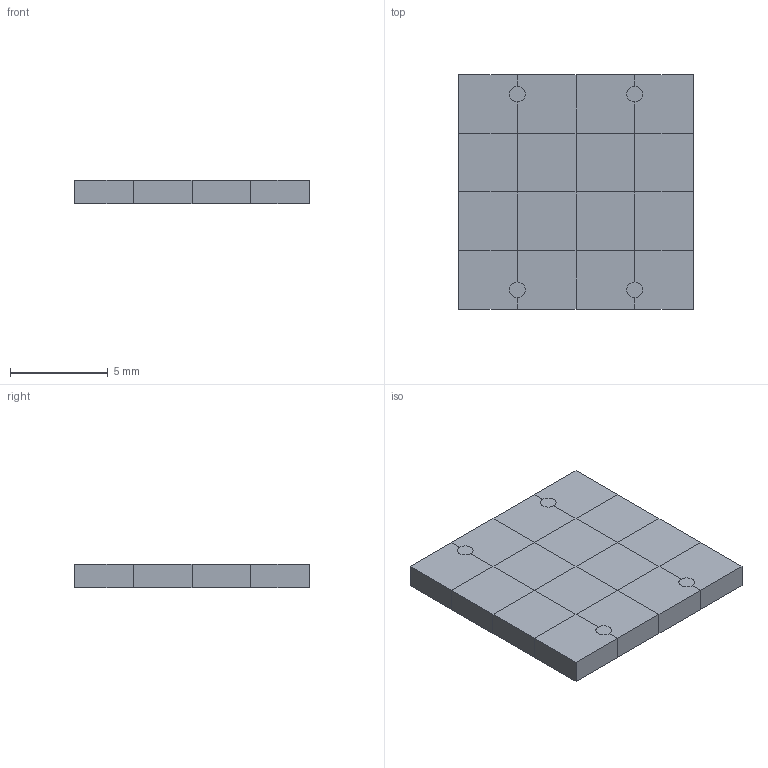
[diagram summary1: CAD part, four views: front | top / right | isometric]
STEP (ISO 10303-21) file: header records copied from the file, then geometry measured from it (millimetres).
FILE_DESCRIPTION(('Open CASCADE Model'),'2;1');
FILE_NAME('Open CASCADE Shape Model','2026-11-20T08:25:56',('Author'),( 'Open CASCADE'),'Open CASCADE STEP processor 7.9','Open CASCADE 7.9' ,'Unknown');
FILE_SCHEMA(('AUTOMOTIVE_DESIGN { 1 0 10303 214 1 1 1 1 }'));
Length unit declared in the file: millimetre
Products named in the file (3): manifold_B7; fluid; solid
Assembly tree (2 placements, depth 2):
  manifold_B7
    fluid
    solid
Bounding box: 12 x 12 x 1.2 mm (x, y, z)
Volume: 172.8 mm3; surface area: 1434.4 mm2
Topology: 2 solids, 2 shells, 1096 faces, 3960 edges, 2194 vertices
Faces by surface type: plane 1088, cylinder 8
Full cylindrical faces by diameter (mm): 0.8 x8
Entity records: 92590 total; most frequent: CARTESIAN_POINT 15221, DIRECTION 14094, LINE 11832, VECTOR 11832, ORIENTED_EDGE 7920, PCURVE 7920, DEFINITIONAL_REPRESENTATION 7920, EDGE_CURVE 3960
One B-rep face of a CAD part: STEP entity #49374.
In plain terms, the planar face has unit normal (0, 0, 1).
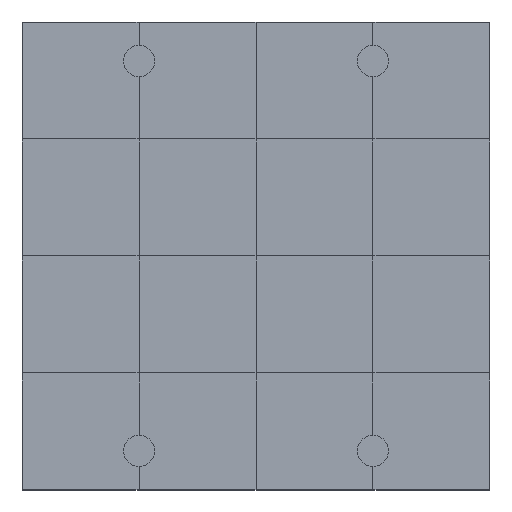
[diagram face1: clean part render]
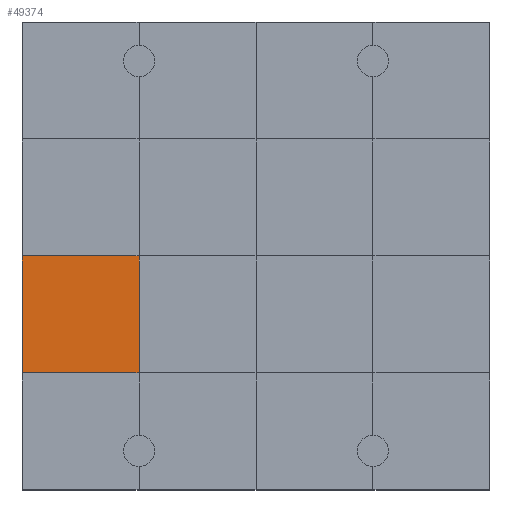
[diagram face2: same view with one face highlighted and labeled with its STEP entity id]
Its self-contained STEP definition (entity closure, numbers rounded to 3 decimals):
#48924 = VERTEX_POINT('',#48925);
#48925 = CARTESIAN_POINT('',(0.,3.,1.2));
#48939 = PLANE('',#48940);
#48940 = AXIS2_PLACEMENT_3D('',#48941,#48942,#48943);
#48941 = CARTESIAN_POINT('',(0.,3.,0.));
#48942 = DIRECTION('',(1.,0.,-0.));
#48943 = DIRECTION('',(0.,0.,1.));
#48965 = PLANE('',#48966);
#48966 = AXIS2_PLACEMENT_3D('',#48967,#48968,#48969);
#48967 = CARTESIAN_POINT('',(0.,0.,1.2));
#48968 = DIRECTION('',(0.,0.,1.));
#48969 = DIRECTION('',(1.,0.,-0.));
#49116 = VERTEX_POINT('',#49117);
#49117 = CARTESIAN_POINT('',(3.,3.,1.2));
#49138 = EDGE_CURVE('',#48924,#49116,#49139,.T.);
#49139 = SURFACE_CURVE('',#49140,(#49144,#49151),.PCURVE_S1.);
#49140 = LINE('',#49141,#49142);
#49141 = CARTESIAN_POINT('',(0.,3.,1.2));
#49142 = VECTOR('',#49143,1.);
#49143 = DIRECTION('',(1.,0.,-0.));
#49144 = PCURVE('',#48965,#49145);
#49145 = DEFINITIONAL_REPRESENTATION('',(#49146),#49150);
#49146 = LINE('',#49147,#49148);
#49147 = CARTESIAN_POINT('',(0.,3.));
#49148 = VECTOR('',#49149,1.);
#49149 = DIRECTION('',(1.,0.));
#49150 = ( GEOMETRIC_REPRESENTATION_CONTEXT(2) 
PARAMETRIC_REPRESENTATION_CONTEXT() REPRESENTATION_CONTEXT('2D SPACE',''
  ) );
#49151 = PCURVE('',#49152,#49157);
#49152 = PLANE('',#49153);
#49153 = AXIS2_PLACEMENT_3D('',#49154,#49155,#49156);
#49154 = CARTESIAN_POINT('',(0.,3.,1.2));
#49155 = DIRECTION('',(0.,0.,1.));
#49156 = DIRECTION('',(1.,0.,-0.));
#49157 = DEFINITIONAL_REPRESENTATION('',(#49158),#49162);
#49158 = LINE('',#49159,#49160);
#49159 = CARTESIAN_POINT('',(0.,0.));
#49160 = VECTOR('',#49161,1.);
#49161 = DIRECTION('',(1.,0.));
#49162 = ( GEOMETRIC_REPRESENTATION_CONTEXT(2) 
PARAMETRIC_REPRESENTATION_CONTEXT() REPRESENTATION_CONTEXT('2D SPACE',''
  ) );
#49197 = VERTEX_POINT('',#49198);
#49198 = CARTESIAN_POINT('',(0.,6.,1.2));
#49224 = EDGE_CURVE('',#48924,#49197,#49225,.T.);
#49225 = SURFACE_CURVE('',#49226,(#49230,#49237),.PCURVE_S1.);
#49226 = LINE('',#49227,#49228);
#49227 = CARTESIAN_POINT('',(0.,3.,1.2));
#49228 = VECTOR('',#49229,1.);
#49229 = DIRECTION('',(-0.,1.,0.));
#49230 = PCURVE('',#48939,#49231);
#49231 = DEFINITIONAL_REPRESENTATION('',(#49232),#49236);
#49232 = LINE('',#49233,#49234);
#49233 = CARTESIAN_POINT('',(1.2,0.));
#49234 = VECTOR('',#49235,1.);
#49235 = DIRECTION('',(0.,-1.));
#49236 = ( GEOMETRIC_REPRESENTATION_CONTEXT(2) 
PARAMETRIC_REPRESENTATION_CONTEXT() REPRESENTATION_CONTEXT('2D SPACE',''
  ) );
#49237 = PCURVE('',#49152,#49238);
#49238 = DEFINITIONAL_REPRESENTATION('',(#49239),#49243);
#49239 = LINE('',#49240,#49241);
#49240 = CARTESIAN_POINT('',(0.,0.));
#49241 = VECTOR('',#49242,1.);
#49242 = DIRECTION('',(0.,1.));
#49243 = ( GEOMETRIC_REPRESENTATION_CONTEXT(2) 
PARAMETRIC_REPRESENTATION_CONTEXT() REPRESENTATION_CONTEXT('2D SPACE',''
  ) );
#49374 = ADVANCED_FACE('',(#49375),#49152,.T.);
#49375 = FACE_BOUND('',#49376,.T.);
#49376 = EDGE_LOOP('',(#49377,#49378,#49379,#49407));
#49377 = ORIENTED_EDGE('',*,*,#49224,.F.);
#49378 = ORIENTED_EDGE('',*,*,#49138,.T.);
#49379 = ORIENTED_EDGE('',*,*,#49380,.T.);
#49380 = EDGE_CURVE('',#49116,#49381,#49383,.T.);
#49381 = VERTEX_POINT('',#49382);
#49382 = CARTESIAN_POINT('',(3.,6.,1.2));
#49383 = SURFACE_CURVE('',#49384,(#49388,#49395),.PCURVE_S1.);
#49384 = LINE('',#49385,#49386);
#49385 = CARTESIAN_POINT('',(3.,3.,1.2));
#49386 = VECTOR('',#49387,1.);
#49387 = DIRECTION('',(-0.,1.,0.));
#49388 = PCURVE('',#49152,#49389);
#49389 = DEFINITIONAL_REPRESENTATION('',(#49390),#49394);
#49390 = LINE('',#49391,#49392);
#49391 = CARTESIAN_POINT('',(3.,0.));
#49392 = VECTOR('',#49393,1.);
#49393 = DIRECTION('',(0.,1.));
#49394 = ( GEOMETRIC_REPRESENTATION_CONTEXT(2) 
PARAMETRIC_REPRESENTATION_CONTEXT() REPRESENTATION_CONTEXT('2D SPACE',''
  ) );
#49395 = PCURVE('',#49396,#49401);
#49396 = PLANE('',#49397);
#49397 = AXIS2_PLACEMENT_3D('',#49398,#49399,#49400);
#49398 = CARTESIAN_POINT('',(3.,3.,1.2));
#49399 = DIRECTION('',(0.,0.,1.));
#49400 = DIRECTION('',(1.,0.,-0.));
#49401 = DEFINITIONAL_REPRESENTATION('',(#49402),#49406);
#49402 = LINE('',#49403,#49404);
#49403 = CARTESIAN_POINT('',(0.,0.));
#49404 = VECTOR('',#49405,1.);
#49405 = DIRECTION('',(0.,1.));
#49406 = ( GEOMETRIC_REPRESENTATION_CONTEXT(2) 
PARAMETRIC_REPRESENTATION_CONTEXT() REPRESENTATION_CONTEXT('2D SPACE',''
  ) );
#49407 = ORIENTED_EDGE('',*,*,#49408,.F.);
#49408 = EDGE_CURVE('',#49197,#49381,#49409,.T.);
#49409 = SURFACE_CURVE('',#49410,(#49414,#49421),.PCURVE_S1.);
#49410 = LINE('',#49411,#49412);
#49411 = CARTESIAN_POINT('',(0.,6.,1.2));
#49412 = VECTOR('',#49413,1.);
#49413 = DIRECTION('',(1.,0.,-0.));
#49414 = PCURVE('',#49152,#49415);
#49415 = DEFINITIONAL_REPRESENTATION('',(#49416),#49420);
#49416 = LINE('',#49417,#49418);
#49417 = CARTESIAN_POINT('',(0.,3.));
#49418 = VECTOR('',#49419,1.);
#49419 = DIRECTION('',(1.,0.));
#49420 = ( GEOMETRIC_REPRESENTATION_CONTEXT(2) 
PARAMETRIC_REPRESENTATION_CONTEXT() REPRESENTATION_CONTEXT('2D SPACE',''
  ) );
#49421 = PCURVE('',#49422,#49427);
#49422 = PLANE('',#49423);
#49423 = AXIS2_PLACEMENT_3D('',#49424,#49425,#49426);
#49424 = CARTESIAN_POINT('',(0.,6.,1.2));
#49425 = DIRECTION('',(0.,0.,1.));
#49426 = DIRECTION('',(1.,0.,-0.));
#49427 = DEFINITIONAL_REPRESENTATION('',(#49428),#49432);
#49428 = LINE('',#49429,#49430);
#49429 = CARTESIAN_POINT('',(0.,0.));
#49430 = VECTOR('',#49431,1.);
#49431 = DIRECTION('',(1.,0.));
#49432 = ( GEOMETRIC_REPRESENTATION_CONTEXT(2) 
PARAMETRIC_REPRESENTATION_CONTEXT() REPRESENTATION_CONTEXT('2D SPACE',''
  ) );
